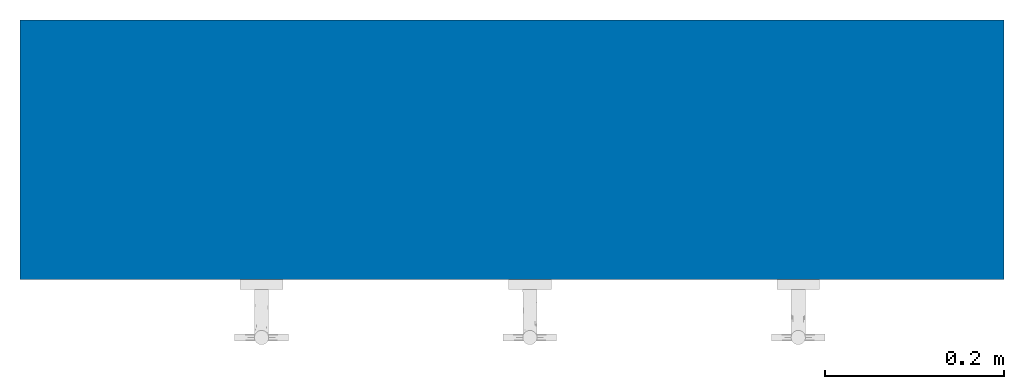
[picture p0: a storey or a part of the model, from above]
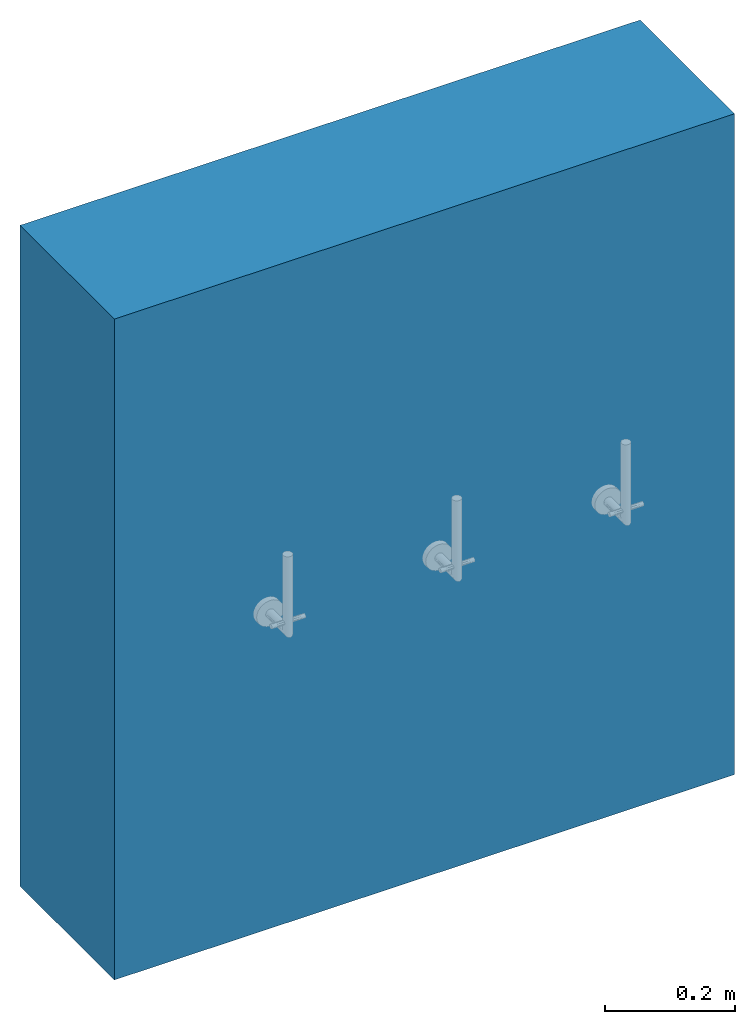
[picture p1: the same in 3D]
Properties of the parts of a building model (IFC2X3)

# File
Description: ViewDefinition [CoordinationView_V2.0]
File name: Project Number
Time: 2021-04-16T12:41:29
Written by: The EXPRESS Data Manager Version 5.02.0100.07 : 28 Aug 2013
Made in: 20170223_1515(x64) - Exporter 18.0.0.420 - Alternate UI 18.0.0.420
Comment: STEP Physical File produced by: The EXPRESS Data Manager Version 5.02.0100.07 : 28 Aug 2013 * Module: EDMstepFileFactory/EDMstandAlone * Creation date: Fri Apr 16 12:41:29 2021 * Host: DESKTOP-KN3O7NT * Database: C:\Users\SARAHS~1\AppData\Local\Temp\{34B5DCA5-469C-49FD-B971-495663B20D7B}\ifc * Database version: 5507 * Database creation date: Fri Apr 16 12:41:27 2021 * Schema: IFC2X3 * Model: DataRepository.ifc * Model creation date: Fri Apr 16 12:41:28 2021 * Header model: DataRepository.ifc_HeaderModel * Header model creation date: Fri Apr 16 12:41:28 2021 * EDMuser: sdai-user * EDMgroup: sdai-group * License ID and type: 5605 : Permanent license. Expiry date: * EDMstepFileFactory options: 020000

# IfcProject, Project Number
LongName: Project Name; Phase: Project Status

# IfcSite, Default
RefLatitude: 51, 30, 23, 112487; RefLongitude: 0, -7, -37, -956022; RefElevation: 0 mm

# IfcBuilding
Pset_BuildingCommon - NumberOfStoreys: 1

# IfcBuildingStorey, Level 0
LongName: Level 0; Elevation: 0 mm

# IfcBuildingElementProxy: Brushed Stainless Steel, Duten_PprRllDpnsrs_H107:Brushed Stainless Steel:324803
In: Level 0
Type - PredefinedType: USERDEFINED; Classification: E2020200 Furniture & Accessories (Uniformat); Material: Duten_Metal_BrushedStainlessSteel
Pset_BuildingElementProxyCommon - Reference: n/a
Pset_ManufacturerTypeInformation - ModelReference: Brushed Stainless Steel; Manufacturer: Duten

# IfcBuildingElementProxy: Matte Black, Duten_PprRllDpnsrs_H107:Matte Black:317954
In: Level 0
Type - PredefinedType: USERDEFINED; Classification: E2020200 Furniture & Accessories (Uniformat); Material: Duten_Metal_MatteBlack
Pset_BuildingElementProxyCommon - Reference: n/a
Pset_ManufacturerTypeInformation - ModelReference: Matte Black Stainless Steel; Manufacturer: Duten

# IfcBuildingElementProxy: Polished Stainless Steel, Duten_PprRllDpnsrs_H107:Polished Stainless Steel:324617
In: Level 0
Type - PredefinedType: USERDEFINED; Classification: E2020200 Furniture & Accessories (Uniformat); Material: Duten_Metal_Polished
Pset_BuildingElementProxyCommon - Reference: n/a
Pset_ManufacturerTypeInformation - ModelReference: Polished Stainless steel; Manufacturer: Duten

# IfcWallStandardCase: Basic Wall:Wall-Ext_102Bwk-75Ins-100LBlk-12P, Basic Wall:Wall-Ext_102Bwk-75Ins-100LBlk-12P:310493
In: Level 0
Type - PredefinedType: STANDARD; Material: Brick, Common 102.5 mm, Fiberglass Batt 75 mm, Concrete Masonry Units _Low Density 100 mm, Plaster 12.5 mm
Pset_WallCommon - Reference: Wall-Ext_102Bwk-75Ins-100LBlk-12P; LoadBearing: no; ExtendToStructure: no; IsExternal: yes; ThermalTransmittance: 0.235926 kg/K/s3
